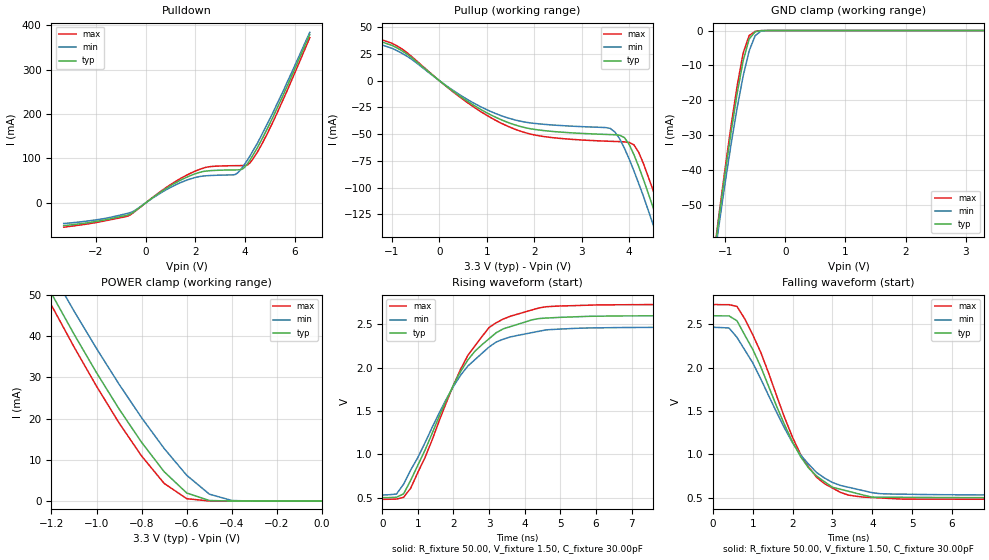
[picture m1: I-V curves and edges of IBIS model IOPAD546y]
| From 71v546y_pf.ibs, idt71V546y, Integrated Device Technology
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|IOIN   NC   NC   NC   NC
|OC   NC   NC   NC   NC
|IN   NC   NC   NC   NC
|CLK   NC   NC   NC   NC
|   Model IOPAD546y
[Model]   IOPAD546y
Model_type   I/O
Polarity   Non-Inverting
Enable   Active-High
Vinl =  0.800V
Vinh =  2.000V
Vmeas =  1.500V
Vref = 1.50   | AC Test Load as shown
Rref = 50.00   | in the datasheet
Cref = 0.00
C_comp   2.00pF   1.56pF   3.00pF
[Temperature Range]   25.00   70.00   0.000
[Voltage Range]   3.30V   3.13V   3.46V
[Pullup Reference]   3.30V   3.13V   3.46V
[Pulldown Reference]   0.000V   0.000V   0.000V
[POWER Clamp Reference]   3.30V   3.13V   3.46V
[GND Clamp Reference]   0.000V   0.000V   0.000V
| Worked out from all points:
|   slope of the pulldown table from 0 to 0.495 V, typ, clamps not added: 24.4 ohm
|   slope of the pullup table from 0 to 0.495 V, typ, clamps not added: 30.2 ohm
|   GND clamp passes 1 mA (typ) near -0.53 V on its own axis
|   POWER clamp passes 1 mA (typ) near -0.55 V on its own axis
|   rising waveform, R_fixture 50.00, V_fixture 1.50, C_fixture 30.00pF: 20-80 % time 1.53ns typ, 1.63ns min, 1.49ns max; typ from 0.502 V to 2.6 V
|   falling waveform, R_fixture 50.00, V_fixture 1.50, C_fixture 30.00pF: 20-80 % time 1.25ns typ, 1.38ns min, 1.2ns max; typ from 2.6 V to 0.502 V
[Pulldown]
| voltage   I(typ)   I(min)   I(max)
-3.3V     -51.3mA    -46.5mA    -54.7mA
-1.9V     -40.9mA    -37.4mA    -43.3mA
-700mV    -26.97mA   -23.12mA   -29.28mA
900mV     35.18mA    31.83mA    37.43mA
1.9V      63.55mA    55.68mA    69.18mA
2.5V      72.06mA    61.25mA    80.87mA
3.7V      74.27mA    67.46mA    83.81mA
3.9V      76.36mA    80.71mA    83.94mA
4.1V      88.72mA    97.22mA    85.48mA
4.5V      125mA      135mA      115mA
5.3V      215mA      225mA      204mA
6.6V      379mA      384mA      372mA
[Pullup]
| voltage   I(typ)   I(min)   I(max)
-3.3V     46.6mA     42.9mA     48.5mA
-1.5V     40.45mA    37.6mA     42.52mA
-800mV    28.21mA    25.82mA    29.95mA
600mV     -19.49mA   -17.84mA   -20.82mA
1.5V      -40mA      -35.64mA   -43.77mA
3.6V      -50.46mA   -44.68mA   -56.75mA
3.9V      -53.31mA   -63.21mA   -57.24mA
4.1V      -69.22mA   -84.36mA   -60.05mA
4.5V      -118mA     -134mA     -102mA
4.7V      -146mA     -161mA     -129mA
4.9V      -174mA     -189mA     -157mA
6.6V      -425mA     -434mA     -412mA
[GND_clamp]
| voltage   I(typ)   I(min)   I(max)
-3.3V     -372mA     -364mA     -378mA
-1.2V     -66.68mA   -68.09mA   -66.18mA
-1.1V     -53.57mA   -55.7mA    -52.65mA
-1V       -40.98mA   -43.82mA   -39.6mA
-900mV    -29.07mA   -32.6mA    -27.25mA
-800mV    -18.12mA   -22.24mA   -15.94mA
-700mV    -8.681mA   -13.05mA   -6.453mA
-600mV    -2.453mA   -5.846mA   -1.446mA
-500mV    -350uA     -1.468mA   -224uA
-400mV    -23.54uA   -126uA     -11.28uA
-300mV    -1.604uA   -8.508uA   -592nA
3.3V      33.53nA    397nA      33.08nA
[POWER_clamp]
| voltage   I(typ)   I(min)   I(max)
-3.3V     304mA      299mA      309mA
-1.3V     60.57mA    65.47mA    58.02mA
-1.2V     50.33mA    55.61mA    47.48mA
-1.1V     40.49mA    46.1mA     37.4mA
-1V       31.13mA    36.99mA    27.85mA
-900mV    22.33mA    28.33mA    18.94mA
-800mV    14.24mA    20.2mA     10.92mA
-700mV    7.123mA    12.75mA    4.291mA
-600mV    1.972mA    6.256mA    594uA
-500mV    154uA      1.7mA      32.23uA
-400mV    9.093uA    150uA      2.047uA
0V        33.53nA    37.86nA    34.75nA
[Ramp]
| variable   typ   min   max
dV/dt_r   1.15/0.91n   1.03/1.00n   1.25/0.84n
dV/dt_f   1.30/0.73n   1.18/0.84n   1.39/0.65n
R_load = 50.00
[Rising Waveform]
R_fixture = 50.00
V_fixture = 1.50
C_fixture = 30.00pF
R_dut = 0.75
L_dut = 0.10nH
C_dut = 0.53pF
| time   V(typ)   V(min)   V(max)
0s        502mV      533mV      483mV
400ps     507mV      544mV      486mV
600ps     546mV      658mV      506mV
800ps     703mV      821mV      612mV
2.2ns     1.954V     1.911V     1.98V
2.6ns     2.187V     2.09V      2.249V
3ns       2.332V     2.237V     2.461V
3.4ns     2.446V     2.327V     2.559V
4.4ns     2.564V     2.418V     2.686V
19.8ns    2.597V     2.464V     2.726V
[Falling Waveform]
R_fixture = 50.00
V_fixture = 1.50
C_fixture = 30.00pF
R_dut = 0.75
L_dut = 0.10nH
C_dut = 0.53pF
| time   V(typ)   V(min)   V(max)
0s        2.597V     2.464V     2.726V
400ps     2.595V     2.456V     2.724V
600ps     2.539V     2.348V     2.704V
1.2ns     2.007V     1.867V     2.173V
1.8ns     1.338V     1.299V     1.42V
2.2ns     974mV      993mV      999mV
2.6ns     752mV      792mV      738mV
3.4ns     576mV      622mV      532mV
5.2ns     505mV      539mV      485mV
19.8ns    502mV      533mV      483mV
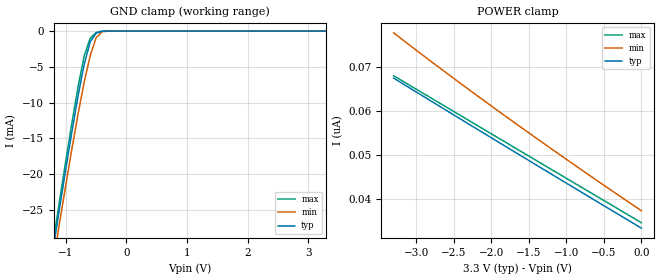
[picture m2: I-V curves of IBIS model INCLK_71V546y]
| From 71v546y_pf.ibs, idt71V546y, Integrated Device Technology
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|   Model INCLK_71V546y
[Model]   INCLK_71V546y
Model_type   Input
Polarity   Non-Inverting
Vinl =  0.8V
Vinh =  2.0V
Vmeas =  1.500V
C_comp   2.00pF   1.56pF   3.00pF
[Temperature Range]   25.00   70.00   0.000
[Voltage Range]   3.30V   3.13V   3.46V
[Pullup Reference]   3.30V   3.13V   3.46V
[Pulldown Reference]   0.000V   0.000V   0.000V
[POWER Clamp Reference]   3.30V   3.13V   3.46V
[GND Clamp Reference]   0.000V   0.000V   0.000V
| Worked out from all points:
|   GND clamp passes 1 mA (typ) near -0.56 V on its own axis
[GND_clamp]
| voltage   I(typ)   I(min)   I(max)
-3.3V     -153mA     -152mA     -153mA
-1.2V     -29.9mA    -31.8mA    -28.95mA
-1.1V     -24.47mA   -26.53mA   -23.41mA
-1V       -19.15mA   -21.38mA   -18mA
-900mV    -14mA      -16.39mA   -12.76mA
-800mV    -9.097mA   -11.61mA   -7.803mA
-700mV    -4.691mA   -7.18mA    -3.52mA
-600mV    -1.52mA    -3.48mA    -1.01mA
-500mV    -275uA     -917uA     -189uA
-400mV    -20.39uA   -90.94uA   -9.996uA
-300mV    -1.424uA   -6.817uA   -531nA
3.3V      33.51nA    39.35nA    33.09nA
[POWER_clamp]
| voltage   I(typ)   I(min)   I(max)
-3.3V     67.41nA    77.64nA    67.95nA
-2.6V     60.13nA    68.62nA    60.89nA
-1.8V     51.89nA    58.68nA    52.83nA
-800mV    41.65nA    46.72nA    42.77nA
0V        33.51nA    37.45nA    34.74nA
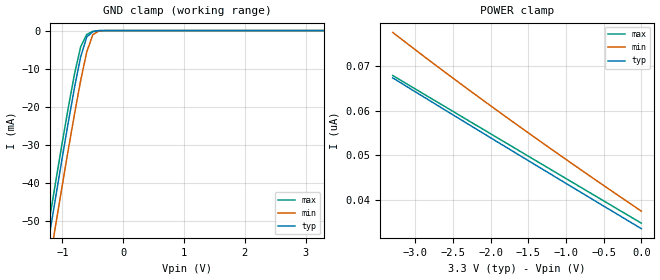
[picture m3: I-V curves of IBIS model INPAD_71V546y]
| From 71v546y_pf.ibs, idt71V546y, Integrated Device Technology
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|   Model INPAD_71V546y
[Model]   INPAD_71V546y
Model_type   Input
Polarity   Non-Inverting
Vinl =  0.8V
Vinh =  2.0V
Vmeas =  1.500V
C_comp   2.00pF   1.56pF   3.00pF
[Temperature Range]   25.00   70.00   0.000
[Voltage Range]   3.30V   3.13V   3.46V
[Pullup Reference]   3.30V   3.13V   3.46V
[Pulldown Reference]   0.000V   0.000V   0.000V
[POWER Clamp Reference]   3.30V   3.13V   3.46V
[GND Clamp Reference]   0.000V   0.000V   0.000V
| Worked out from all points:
|   GND clamp passes 1 mA (typ) near -0.55 V on its own axis
[GND_clamp]
| voltage   I(typ)   I(min)   I(max)
-3.3V     -264mA     -271mA     -260mA
-1.3V     -62.17mA   -69.54mA   -58.12mA
-1.2V     -52.37mA   -59.74mA   -48.34mA
-1.1V     -42.67mA   -50.02mA   -38.65mA
-900mV    -23.78mA   -30.97mA   -19.92mA
-800mV    -14.87mA   -21.81mA   -11.29mA
-700mV    -6.924mA   -13.14mA   -4.258mA
-600mV    -1.699mA   -5.623mA   -1.019mA
-500mV    -276uA     -1.078mA   -189uA
-400mV    -20.39uA   -91.67uA   -9.996uA
-300mV    -1.424uA   -6.819uA   -531nA
3.3V      33.51nA    39.35nA    33.09nA
[POWER_clamp]
| voltage   I(typ)   I(min)   I(max)
-3.3V     67.41nA    77.64nA    67.95nA
-2.6V     60.13nA    68.62nA    60.89nA
-1.8V     51.89nA    58.68nA    52.83nA
-800mV    41.65nA    46.72nA    42.77nA
0V        33.51nA    37.45nA    34.74nA
